VERSION 5.7 ;
  NOWIREEXTENSIONATPIN ON ;
  DIVIDERCHAR "/" ;
  BUSBITCHARS "[]" ;
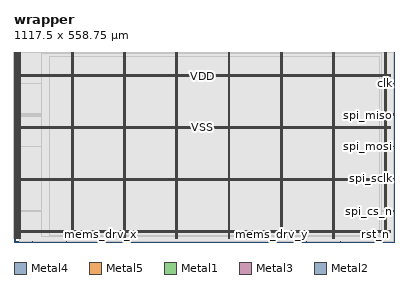
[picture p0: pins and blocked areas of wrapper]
MACRO wrapper
  CLASS BLOCK ;
  FOREIGN wrapper ;
  ORIGIN 0.000 0.000 ;
  SIZE 1117.500 BY 558.750 ;
  PIN VDD
    DIRECTION INOUT ;
    USE POWER ;
    PORT
      LAYER Metal4 ;
        RECT 15.520 11.460 17.120 556.940 ;
    END
    PORT
      LAYER Metal4 ;
        RECT 169.120 11.460 170.720 556.940 ;
    END
    PORT
      LAYER Metal4 ;
        RECT 322.720 11.460 324.320 556.940 ;
    END
    PORT
      LAYER Metal4 ;
        RECT 476.320 11.460 477.920 556.940 ;
    END
    PORT
      LAYER Metal4 ;
        RECT 629.920 11.460 631.520 556.940 ;
    END
    PORT
      LAYER Metal4 ;
        RECT 783.520 11.460 785.120 556.940 ;
    END
    PORT
      LAYER Metal4 ;
        RECT 937.120 11.460 938.720 556.940 ;
    END
    PORT
      LAYER Metal4 ;
        RECT 1090.720 11.460 1092.320 556.940 ;
    END
    PORT
      LAYER Metal5 ;
        RECT 0.000 27.610 1107.120 29.210 ;
    END
    PORT
      LAYER Metal5 ;
        RECT 0.000 180.790 1107.120 182.390 ;
    END
    PORT
      LAYER Metal5 ;
        RECT 0.000 333.970 1107.120 335.570 ;
    END
    PORT
      LAYER Metal5 ;
        RECT 0.000 487.150 1107.120 488.750 ;
    END
    PORT
      LAYER Metal1 ;
        RECT 0.000 15.380 15.670 15.980 ;
    END
    PORT
      LAYER Metal1 ;
        RECT 0.000 23.220 15.670 23.820 ;
    END
    PORT
      LAYER Metal1 ;
        RECT 0.000 31.060 15.670 31.660 ;
    END
    PORT
      LAYER Metal1 ;
        RECT 0.000 38.900 15.670 39.500 ;
    END
    PORT
      LAYER Metal1 ;
        RECT 0.000 46.740 15.670 47.340 ;
    END
    PORT
      LAYER Metal1 ;
        RECT 0.000 54.580 15.670 55.180 ;
    END
    PORT
      LAYER Metal1 ;
        RECT 0.000 62.420 15.670 63.020 ;
    END
    PORT
      LAYER Metal1 ;
        RECT 0.000 70.260 15.670 70.860 ;
    END
    PORT
      LAYER Metal1 ;
        RECT 0.000 78.100 15.670 78.700 ;
    END
    PORT
      LAYER Metal1 ;
        RECT 0.000 85.940 15.670 86.540 ;
    END
    PORT
      LAYER Metal1 ;
        RECT 0.000 93.780 15.670 94.380 ;
    END
    PORT
      LAYER Metal1 ;
        RECT 0.000 101.620 15.670 102.220 ;
    END
    PORT
      LAYER Metal1 ;
        RECT 0.000 109.460 15.670 110.060 ;
    END
    PORT
      LAYER Metal1 ;
        RECT 0.000 117.300 15.670 117.900 ;
    END
    PORT
      LAYER Metal1 ;
        RECT 0.000 125.140 15.670 125.740 ;
    END
    PORT
      LAYER Metal1 ;
        RECT 0.000 132.980 15.670 133.580 ;
    END
    PORT
      LAYER Metal1 ;
        RECT 0.000 140.820 15.670 141.420 ;
    END
    PORT
      LAYER Metal1 ;
        RECT 0.000 148.660 15.670 149.260 ;
    END
    PORT
      LAYER Metal1 ;
        RECT 0.000 156.500 15.670 157.100 ;
    END
    PORT
      LAYER Metal1 ;
        RECT 0.000 164.340 15.670 164.940 ;
    END
    PORT
      LAYER Metal1 ;
        RECT 0.000 172.180 15.670 172.780 ;
    END
    PORT
      LAYER Metal1 ;
        RECT 0.000 180.020 15.670 180.620 ;
    END
    PORT
      LAYER Metal1 ;
        RECT 0.000 187.860 15.670 188.460 ;
    END
    PORT
      LAYER Metal1 ;
        RECT 0.000 195.700 15.670 196.300 ;
    END
    PORT
      LAYER Metal1 ;
        RECT 0.000 203.540 15.670 204.140 ;
    END
    PORT
      LAYER Metal1 ;
        RECT 0.000 211.380 15.670 211.980 ;
    END
    PORT
      LAYER Metal1 ;
        RECT 0.000 219.220 15.670 219.820 ;
    END
    PORT
      LAYER Metal1 ;
        RECT 0.000 227.060 15.670 227.660 ;
    END
    PORT
      LAYER Metal1 ;
        RECT 0.000 234.900 15.670 235.500 ;
    END
    PORT
      LAYER Metal1 ;
        RECT 0.000 242.740 15.670 243.340 ;
    END
    PORT
      LAYER Metal1 ;
        RECT 0.000 250.580 15.670 251.180 ;
    END
    PORT
      LAYER Metal1 ;
        RECT 0.000 258.420 15.670 259.020 ;
    END
    PORT
      LAYER Metal1 ;
        RECT 0.000 266.260 15.670 266.860 ;
    END
    PORT
      LAYER Metal1 ;
        RECT 0.000 274.100 15.670 274.700 ;
    END
    PORT
      LAYER Metal1 ;
        RECT 0.000 281.940 15.670 282.540 ;
    END
    PORT
      LAYER Metal1 ;
        RECT 0.000 289.780 15.670 290.380 ;
    END
    PORT
      LAYER Metal1 ;
        RECT 0.000 297.620 15.670 298.220 ;
    END
    PORT
      LAYER Metal1 ;
        RECT 0.000 305.460 15.670 306.060 ;
    END
    PORT
      LAYER Metal1 ;
        RECT 0.000 313.300 15.670 313.900 ;
    END
    PORT
      LAYER Metal1 ;
        RECT 0.000 321.140 15.670 321.740 ;
    END
    PORT
      LAYER Metal1 ;
        RECT 0.000 328.980 15.670 329.580 ;
    END
    PORT
      LAYER Metal1 ;
        RECT 0.000 336.820 15.670 337.420 ;
    END
    PORT
      LAYER Metal1 ;
        RECT 0.000 344.660 15.670 345.260 ;
    END
    PORT
      LAYER Metal1 ;
        RECT 0.000 352.500 15.670 353.100 ;
    END
    PORT
      LAYER Metal1 ;
        RECT 0.000 360.340 15.670 360.940 ;
    END
    PORT
      LAYER Metal1 ;
        RECT 0.000 368.180 15.670 368.780 ;
    END
    PORT
      LAYER Metal1 ;
        RECT 0.000 376.020 15.670 376.620 ;
    END
    PORT
      LAYER Metal1 ;
        RECT 0.000 383.860 15.670 384.460 ;
    END
    PORT
      LAYER Metal1 ;
        RECT 0.000 391.700 15.670 392.300 ;
    END
    PORT
      LAYER Metal1 ;
        RECT 0.000 399.540 15.670 400.140 ;
    END
    PORT
      LAYER Metal1 ;
        RECT 0.000 407.380 15.670 407.980 ;
    END
    PORT
      LAYER Metal1 ;
        RECT 0.000 415.220 15.670 415.820 ;
    END
    PORT
      LAYER Metal1 ;
        RECT 0.000 423.060 15.670 423.660 ;
    END
    PORT
      LAYER Metal1 ;
        RECT 0.000 430.900 15.670 431.500 ;
    END
    PORT
      LAYER Metal1 ;
        RECT 0.000 438.740 15.670 439.340 ;
    END
    PORT
      LAYER Metal1 ;
        RECT 0.000 446.580 15.670 447.180 ;
    END
    PORT
      LAYER Metal1 ;
        RECT 0.000 454.420 15.670 455.020 ;
    END
    PORT
      LAYER Metal1 ;
        RECT 0.000 462.260 15.670 462.860 ;
    END
    PORT
      LAYER Metal1 ;
        RECT 0.000 470.100 15.670 470.700 ;
    END
    PORT
      LAYER Metal1 ;
        RECT 0.000 477.940 15.670 478.540 ;
    END
    PORT
      LAYER Metal1 ;
        RECT 0.000 485.780 15.670 486.380 ;
    END
    PORT
      LAYER Metal1 ;
        RECT 0.000 493.620 15.670 494.220 ;
    END
    PORT
      LAYER Metal1 ;
        RECT 0.000 501.460 15.670 502.060 ;
    END
    PORT
      LAYER Metal1 ;
        RECT 0.000 509.300 15.670 509.900 ;
    END
    PORT
      LAYER Metal1 ;
        RECT 0.000 517.140 15.670 517.740 ;
    END
    PORT
      LAYER Metal1 ;
        RECT 0.000 524.980 15.670 525.580 ;
    END
    PORT
      LAYER Metal1 ;
        RECT 0.000 532.820 15.670 533.420 ;
    END
    PORT
      LAYER Metal1 ;
        RECT 0.000 540.660 15.670 541.260 ;
    END
    PORT
      LAYER Metal1 ;
        RECT 0.000 548.500 15.670 549.100 ;
    END
    PORT
      LAYER Metal1 ;
        RECT 0.000 556.340 15.670 556.940 ;
    END
  END VDD
  PIN VSS
    DIRECTION INOUT ;
    USE GROUND ;
    PORT
      LAYER Metal4 ;
        RECT 18.820 11.460 20.420 556.940 ;
    END
    PORT
      LAYER Metal4 ;
        RECT 172.420 11.460 174.020 556.940 ;
    END
    PORT
      LAYER Metal4 ;
        RECT 326.020 11.460 327.620 556.940 ;
    END
    PORT
      LAYER Metal4 ;
        RECT 479.620 11.460 481.220 556.940 ;
    END
    PORT
      LAYER Metal4 ;
        RECT 633.220 11.460 634.820 556.940 ;
    END
    PORT
      LAYER Metal4 ;
        RECT 786.820 11.460 788.420 556.940 ;
    END
    PORT
      LAYER Metal4 ;
        RECT 940.420 11.460 942.020 556.940 ;
    END
    PORT
      LAYER Metal4 ;
        RECT 1094.020 11.460 1095.620 556.940 ;
    END
    PORT
      LAYER Metal5 ;
        RECT 0.000 30.910 1107.120 32.510 ;
    END
    PORT
      LAYER Metal5 ;
        RECT 0.000 184.090 1107.120 185.690 ;
    END
    PORT
      LAYER Metal5 ;
        RECT 0.000 337.270 1107.120 338.870 ;
    END
    PORT
      LAYER Metal5 ;
        RECT 0.000 490.450 1107.120 492.050 ;
    END
    PORT
      LAYER Metal1 ;
        RECT 0.000 11.460 18.970 12.060 ;
    END
    PORT
      LAYER Metal1 ;
        RECT 0.000 19.300 18.970 19.900 ;
    END
    PORT
      LAYER Metal1 ;
        RECT 0.000 27.140 18.970 27.740 ;
    END
    PORT
      LAYER Metal1 ;
        RECT 0.000 34.980 18.970 35.580 ;
    END
    PORT
      LAYER Metal1 ;
        RECT 0.000 42.820 18.970 43.420 ;
    END
    PORT
      LAYER Metal1 ;
        RECT 0.000 50.660 18.970 51.260 ;
    END
    PORT
      LAYER Metal1 ;
        RECT 0.000 58.500 18.970 59.100 ;
    END
    PORT
      LAYER Metal1 ;
        RECT 0.000 66.340 18.970 66.940 ;
    END
    PORT
      LAYER Metal1 ;
        RECT 0.000 74.180 18.970 74.780 ;
    END
    PORT
      LAYER Metal1 ;
        RECT 0.000 82.020 18.970 82.620 ;
    END
    PORT
      LAYER Metal1 ;
        RECT 0.000 89.860 18.970 90.460 ;
    END
    PORT
      LAYER Metal1 ;
        RECT 0.000 97.700 18.970 98.300 ;
    END
    PORT
      LAYER Metal1 ;
        RECT 0.000 105.540 18.970 106.140 ;
    END
    PORT
      LAYER Metal1 ;
        RECT 0.000 113.380 18.970 113.980 ;
    END
    PORT
      LAYER Metal1 ;
        RECT 0.000 121.220 18.970 121.820 ;
    END
    PORT
      LAYER Metal1 ;
        RECT 0.000 129.060 18.970 129.660 ;
    END
    PORT
      LAYER Metal1 ;
        RECT 0.000 136.900 18.970 137.500 ;
    END
    PORT
      LAYER Metal1 ;
        RECT 0.000 144.740 18.970 145.340 ;
    END
    PORT
      LAYER Metal1 ;
        RECT 0.000 152.580 18.970 153.180 ;
    END
    PORT
      LAYER Metal1 ;
        RECT 0.000 160.420 18.970 161.020 ;
    END
    PORT
      LAYER Metal1 ;
        RECT 0.000 168.260 18.970 168.860 ;
    END
    PORT
      LAYER Metal1 ;
        RECT 0.000 176.100 18.970 176.700 ;
    END
    PORT
      LAYER Metal1 ;
        RECT 0.000 183.940 18.970 184.540 ;
    END
    PORT
      LAYER Metal1 ;
        RECT 0.000 191.780 18.970 192.380 ;
    END
    PORT
      LAYER Metal1 ;
        RECT 0.000 199.620 18.970 200.220 ;
    END
    PORT
      LAYER Metal1 ;
        RECT 0.000 207.460 18.970 208.060 ;
    END
    PORT
      LAYER Metal1 ;
        RECT 0.000 215.300 18.970 215.900 ;
    END
    PORT
      LAYER Metal1 ;
        RECT 0.000 223.140 18.970 223.740 ;
    END
    PORT
      LAYER Metal1 ;
        RECT 0.000 230.980 18.970 231.580 ;
    END
    PORT
      LAYER Metal1 ;
        RECT 0.000 238.820 18.970 239.420 ;
    END
    PORT
      LAYER Metal1 ;
        RECT 0.000 246.660 18.970 247.260 ;
    END
    PORT
      LAYER Metal1 ;
        RECT 0.000 254.500 18.970 255.100 ;
    END
    PORT
      LAYER Metal1 ;
        RECT 0.000 262.340 18.970 262.940 ;
    END
    PORT
      LAYER Metal1 ;
        RECT 0.000 270.180 18.970 270.780 ;
    END
    PORT
      LAYER Metal1 ;
        RECT 0.000 278.020 18.970 278.620 ;
    END
    PORT
      LAYER Metal1 ;
        RECT 0.000 285.860 18.970 286.460 ;
    END
    PORT
      LAYER Metal1 ;
        RECT 0.000 293.700 18.970 294.300 ;
    END
    PORT
      LAYER Metal1 ;
        RECT 0.000 301.540 18.970 302.140 ;
    END
    PORT
      LAYER Metal1 ;
        RECT 0.000 309.380 18.970 309.980 ;
    END
    PORT
      LAYER Metal1 ;
        RECT 0.000 317.220 18.970 317.820 ;
    END
    PORT
      LAYER Metal1 ;
        RECT 0.000 325.060 18.970 325.660 ;
    END
    PORT
      LAYER Metal1 ;
        RECT 0.000 332.900 18.970 333.500 ;
    END
    PORT
      LAYER Metal1 ;
        RECT 0.000 340.740 18.970 341.340 ;
    END
    PORT
      LAYER Metal1 ;
        RECT 0.000 348.580 18.970 349.180 ;
    END
    PORT
      LAYER Metal1 ;
        RECT 0.000 356.420 18.970 357.020 ;
    END
    PORT
      LAYER Metal1 ;
        RECT 0.000 364.260 18.970 364.860 ;
    END
    PORT
      LAYER Metal1 ;
        RECT 0.000 372.100 18.970 372.700 ;
    END
    PORT
      LAYER Metal1 ;
        RECT 0.000 379.940 18.970 380.540 ;
    END
    PORT
      LAYER Metal1 ;
        RECT 0.000 387.780 18.970 388.380 ;
    END
    PORT
      LAYER Metal1 ;
        RECT 0.000 395.620 18.970 396.220 ;
    END
    PORT
      LAYER Metal1 ;
        RECT 0.000 403.460 18.970 404.060 ;
    END
    PORT
      LAYER Metal1 ;
        RECT 0.000 411.300 18.970 411.900 ;
    END
    PORT
      LAYER Metal1 ;
        RECT 0.000 419.140 18.970 419.740 ;
    END
    PORT
      LAYER Metal1 ;
        RECT 0.000 426.980 18.970 427.580 ;
    END
    PORT
      LAYER Metal1 ;
        RECT 0.000 434.820 18.970 435.420 ;
    END
    PORT
      LAYER Metal1 ;
        RECT 0.000 442.660 18.970 443.260 ;
    END
    PORT
      LAYER Metal1 ;
        RECT 0.000 450.500 18.970 451.100 ;
    END
    PORT
      LAYER Metal1 ;
        RECT 0.000 458.340 18.970 458.940 ;
    END
    PORT
      LAYER Metal1 ;
        RECT 0.000 466.180 18.970 466.780 ;
    END
    PORT
      LAYER Metal1 ;
        RECT 0.000 474.020 18.970 474.620 ;
    END
    PORT
      LAYER Metal1 ;
        RECT 0.000 481.860 18.970 482.460 ;
    END
    PORT
      LAYER Metal1 ;
        RECT 0.000 489.700 18.970 490.300 ;
    END
    PORT
      LAYER Metal1 ;
        RECT 0.000 497.540 18.970 498.140 ;
    END
    PORT
      LAYER Metal1 ;
        RECT 0.000 505.380 18.970 505.980 ;
    END
    PORT
      LAYER Metal1 ;
        RECT 0.000 513.220 18.970 513.820 ;
    END
    PORT
      LAYER Metal1 ;
        RECT 0.000 521.060 18.970 521.660 ;
    END
    PORT
      LAYER Metal1 ;
        RECT 0.000 528.900 18.970 529.500 ;
    END
    PORT
      LAYER Metal1 ;
        RECT 0.000 536.740 18.970 537.340 ;
    END
    PORT
      LAYER Metal1 ;
        RECT 0.000 544.580 18.970 545.180 ;
    END
    PORT
      LAYER Metal1 ;
        RECT 0.000 552.420 18.970 553.020 ;
    END
  END VSS
  PIN clk
    DIRECTION INPUT ;
    USE SIGNAL ;
    ANTENNAGATEAREA 9.476000 ;
    ANTENNADIFFAREA 0.820800 ;
    PORT
      LAYER Metal3 ;
        RECT 1116.940 465.920 1117.500 466.480 ;
    END
  END clk
  PIN dir_x
    DIRECTION OUTPUT ;
    USE SIGNAL ;
    ANTENNADIFFAREA 1.182800 ;
    PORT
      LAYER Metal2 ;
        RECT 154.560 0.000 155.120 0.560 ;
    END
  END dir_x
  PIN dir_y
    DIRECTION OUTPUT ;
    USE SIGNAL ;
    ANTENNADIFFAREA 1.182800 ;
    PORT
      LAYER Metal2 ;
        RECT 860.160 0.000 860.720 0.560 ;
    END
  END dir_y
  PIN mems_drv_x
    DIRECTION OUTPUT ;
    USE SIGNAL ;
    ANTENNADIFFAREA 1.182800 ;
    PORT
      LAYER Metal2 ;
        RECT 255.360 0.000 255.920 0.560 ;
    END
  END mems_drv_x
  PIN mems_drv_y
    DIRECTION OUTPUT ;
    USE SIGNAL ;
    ANTENNADIFFAREA 1.182800 ;
    PORT
      LAYER Metal2 ;
        RECT 759.360 0.000 759.920 0.560 ;
    END
  END mems_drv_y
  PIN move_en_x
    DIRECTION OUTPUT ;
    USE SIGNAL ;
    ANTENNADIFFAREA 1.182800 ;
    PORT
      LAYER Metal2 ;
        RECT 53.760 0.000 54.320 0.560 ;
    END
  END move_en_x
  PIN move_en_y
    DIRECTION OUTPUT ;
    USE SIGNAL ;
    ANTENNADIFFAREA 1.182800 ;
    PORT
      LAYER Metal2 ;
        RECT 960.960 0.000 961.520 0.560 ;
    END
  END move_en_y
  PIN rst_n
    DIRECTION INPUT ;
    USE SIGNAL ;
    ANTENNAGATEAREA 0.498500 ;
    ANTENNADIFFAREA 0.410400 ;
    PORT
      LAYER Metal2 ;
        RECT 1061.760 0.000 1062.320 0.560 ;
    END
  END rst_n
  PIN spi_cs_n
    DIRECTION INPUT ;
    USE SIGNAL ;
    ANTENNAGATEAREA 0.498500 ;
    ANTENNADIFFAREA 0.410400 ;
    PORT
      LAYER Metal3 ;
        RECT 1116.940 90.720 1117.500 91.280 ;
    END
  END spi_cs_n
  PIN spi_miso
    DIRECTION OUTPUT ;
    USE SIGNAL ;
    ANTENNADIFFAREA 1.182800 ;
    PORT
      LAYER Metal3 ;
        RECT 1116.940 370.720 1117.500 371.280 ;
    END
  END spi_miso
  PIN spi_miso_oe
    DIRECTION OUTPUT ;
    USE SIGNAL ;
    ANTENNADIFFAREA 1.182800 ;
    PORT
      LAYER Metal3 ;
        RECT 1116.940 376.320 1117.500 376.880 ;
    END
  END spi_miso_oe
  PIN spi_mosi
    DIRECTION INPUT ;
    USE SIGNAL ;
    ANTENNAGATEAREA 0.498500 ;
    ANTENNADIFFAREA 0.410400 ;
    PORT
      LAYER Metal3 ;
        RECT 1116.940 281.120 1117.500 281.680 ;
    END
  END spi_mosi
  PIN spi_sclk
    DIRECTION INPUT ;
    USE SIGNAL ;
    ANTENNAGATEAREA 0.498500 ;
    ANTENNADIFFAREA 0.410400 ;
    PORT
      LAYER Metal3 ;
        RECT 1116.940 185.920 1117.500 186.480 ;
    END
  END spi_sclk
  OBS
      LAYER Nwell ;
        RECT -0.430 554.480 1107.550 557.070 ;
      LAYER Pwell ;
        RECT -0.430 550.960 1107.550 554.480 ;
      LAYER Nwell ;
        RECT -0.430 546.640 1107.550 550.960 ;
      LAYER Pwell ;
        RECT -0.430 543.120 1107.550 546.640 ;
      LAYER Nwell ;
        RECT -0.430 538.800 1107.550 543.120 ;
      LAYER Pwell ;
        RECT -0.430 535.280 1107.550 538.800 ;
      LAYER Nwell ;
        RECT -0.430 530.960 1107.550 535.280 ;
      LAYER Pwell ;
        RECT -0.430 527.440 1107.550 530.960 ;
      LAYER Nwell ;
        RECT -0.430 523.120 1107.550 527.440 ;
      LAYER Pwell ;
        RECT -0.430 519.600 1107.550 523.120 ;
      LAYER Nwell ;
        RECT -0.430 515.280 1107.550 519.600 ;
      LAYER Pwell ;
        RECT -0.430 511.760 1107.550 515.280 ;
      LAYER Nwell ;
        RECT -0.430 507.440 1107.550 511.760 ;
      LAYER Pwell ;
        RECT -0.430 503.920 1107.550 507.440 ;
      LAYER Nwell ;
        RECT -0.430 499.600 1107.550 503.920 ;
      LAYER Pwell ;
        RECT -0.430 496.080 1107.550 499.600 ;
      LAYER Nwell ;
        RECT -0.430 491.760 1107.550 496.080 ;
      LAYER Pwell ;
        RECT -0.430 488.240 1107.550 491.760 ;
      LAYER Nwell ;
        RECT -0.430 483.920 1107.550 488.240 ;
      LAYER Pwell ;
        RECT -0.430 480.400 1107.550 483.920 ;
      LAYER Nwell ;
        RECT -0.430 476.080 1107.550 480.400 ;
      LAYER Pwell ;
        RECT -0.430 472.560 1107.550 476.080 ;
      LAYER Nwell ;
        RECT -0.430 468.240 1107.550 472.560 ;
      LAYER Pwell ;
        RECT -0.430 464.720 1107.550 468.240 ;
      LAYER Nwell ;
        RECT -0.430 460.400 1107.550 464.720 ;
      LAYER Pwell ;
        RECT -0.430 456.880 1107.550 460.400 ;
      LAYER Nwell ;
        RECT -0.430 452.560 1107.550 456.880 ;
      LAYER Pwell ;
        RECT -0.430 449.040 1107.550 452.560 ;
      LAYER Nwell ;
        RECT -0.430 444.720 1107.550 449.040 ;
      LAYER Pwell ;
        RECT -0.430 441.200 1107.550 444.720 ;
      LAYER Nwell ;
        RECT -0.430 436.880 1107.550 441.200 ;
      LAYER Pwell ;
        RECT -0.430 433.360 1107.550 436.880 ;
      LAYER Nwell ;
        RECT -0.430 429.040 1107.550 433.360 ;
      LAYER Pwell ;
        RECT -0.430 425.520 1107.550 429.040 ;
      LAYER Nwell ;
        RECT -0.430 421.200 1107.550 425.520 ;
      LAYER Pwell ;
        RECT -0.430 417.680 1107.550 421.200 ;
      LAYER Nwell ;
        RECT -0.430 413.360 1107.550 417.680 ;
      LAYER Pwell ;
        RECT -0.430 409.840 1107.550 413.360 ;
      LAYER Nwell ;
        RECT -0.430 405.520 1107.550 409.840 ;
      LAYER Pwell ;
        RECT -0.430 402.000 1107.550 405.520 ;
      LAYER Nwell ;
        RECT -0.430 397.680 1107.550 402.000 ;
      LAYER Pwell ;
        RECT -0.430 394.160 1107.550 397.680 ;
      LAYER Nwell ;
        RECT -0.430 389.840 1107.550 394.160 ;
      LAYER Pwell ;
        RECT -0.430 386.320 1107.550 389.840 ;
      LAYER Nwell ;
        RECT -0.430 382.000 1107.550 386.320 ;
      LAYER Pwell ;
        RECT -0.430 378.480 1107.550 382.000 ;
      LAYER Nwell ;
        RECT -0.430 374.160 1107.550 378.480 ;
      LAYER Pwell ;
        RECT -0.430 370.640 1107.550 374.160 ;
      LAYER Nwell ;
        RECT -0.430 366.320 1107.550 370.640 ;
      LAYER Pwell ;
        RECT -0.430 362.800 1107.550 366.320 ;
      LAYER Nwell ;
        RECT -0.430 358.480 1107.550 362.800 ;
      LAYER Pwell ;
        RECT -0.430 354.960 1107.550 358.480 ;
      LAYER Nwell ;
        RECT -0.430 350.640 1107.550 354.960 ;
      LAYER Pwell ;
        RECT -0.430 347.120 1107.550 350.640 ;
      LAYER Nwell ;
        RECT -0.430 342.800 1107.550 347.120 ;
      LAYER Pwell ;
        RECT -0.430 339.280 1107.550 342.800 ;
      LAYER Nwell ;
        RECT -0.430 334.960 1107.550 339.280 ;
      LAYER Pwell ;
        RECT -0.430 331.440 1107.550 334.960 ;
      LAYER Nwell ;
        RECT -0.430 327.120 1107.550 331.440 ;
      LAYER Pwell ;
        RECT -0.430 323.600 1107.550 327.120 ;
      LAYER Nwell ;
        RECT -0.430 319.280 1107.550 323.600 ;
      LAYER Pwell ;
        RECT -0.430 315.760 1107.550 319.280 ;
      LAYER Nwell ;
        RECT -0.430 311.440 1107.550 315.760 ;
      LAYER Pwell ;
        RECT -0.430 307.920 1107.550 311.440 ;
      LAYER Nwell ;
        RECT -0.430 303.600 1107.550 307.920 ;
      LAYER Pwell ;
        RECT -0.430 300.080 1107.550 303.600 ;
      LAYER Nwell ;
        RECT -0.430 295.760 1107.550 300.080 ;
      LAYER Pwell ;
        RECT -0.430 292.240 1107.550 295.760 ;
      LAYER Nwell ;
        RECT -0.430 287.920 1107.550 292.240 ;
      LAYER Pwell ;
        RECT -0.430 284.400 1107.550 287.920 ;
      LAYER Nwell ;
        RECT -0.430 280.080 1107.550 284.400 ;
      LAYER Pwell ;
        RECT -0.430 276.560 1107.550 280.080 ;
      LAYER Nwell ;
        RECT -0.430 272.240 1107.550 276.560 ;
      LAYER Pwell ;
        RECT -0.430 268.720 1107.550 272.240 ;
      LAYER Nwell ;
        RECT -0.430 264.400 1107.550 268.720 ;
      LAYER Pwell ;
        RECT -0.430 260.880 1107.550 264.400 ;
      LAYER Nwell ;
        RECT -0.430 256.560 1107.550 260.880 ;
      LAYER Pwell ;
        RECT -0.430 254.370 1107.550 256.560 ;
        RECT -0.430 253.040 258.030 254.370 ;
      LAYER Nwell ;
        RECT 258.030 253.040 1107.550 254.370 ;
        RECT -0.430 248.720 1107.550 253.040 ;
      LAYER Pwell ;
        RECT -0.430 245.200 258.030 248.720 ;
      LAYER Nwell ;
        RECT 258.030 245.200 1107.550 248.720 ;
        RECT -0.430 240.880 1107.550 245.200 ;
      LAYER Pwell ;
        RECT -0.430 237.360 258.030 240.880 ;
      LAYER Nwell ;
        RECT 258.030 237.360 1107.550 240.880 ;
        RECT -0.430 233.040 1107.550 237.360 ;
      LAYER Pwell ;
        RECT -0.430 229.520 258.030 233.040 ;
      LAYER Nwell ;
        RECT 258.030 229.520 1107.550 233.040 ;
        RECT -0.430 225.200 1107.550 229.520 ;
      LAYER Pwell ;
        RECT -0.430 221.680 258.030 225.200 ;
      LAYER Nwell ;
        RECT 258.030 221.680 1107.550 225.200 ;
        RECT -0.430 217.360 1107.550 221.680 ;
      LAYER Pwell ;
        RECT -0.430 213.840 258.030 217.360 ;
      LAYER Nwell ;
        RECT 258.030 213.840 1107.550 217.360 ;
        RECT -0.430 209.520 1107.550 213.840 ;
      LAYER Pwell ;
        RECT -0.430 206.000 258.030 209.520 ;
      LAYER Nwell ;
        RECT 258.030 206.000 1107.550 209.520 ;
        RECT -0.430 201.680 1107.550 206.000 ;
      LAYER Pwell ;
        RECT -0.430 198.160 258.030 201.680 ;
      LAYER Nwell ;
        RECT 258.030 198.160 1107.550 201.680 ;
        RECT -0.430 193.840 1107.550 198.160 ;
      LAYER Pwell ;
        RECT -0.430 190.320 258.030 193.840 ;
      LAYER Nwell ;
        RECT 258.030 190.320 1107.550 193.840 ;
        RECT -0.430 186.000 1107.550 190.320 ;
      LAYER Pwell ;
        RECT -0.430 182.480 258.030 186.000 ;
      LAYER Nwell ;
        RECT 258.030 182.480 1107.550 186.000 ;
        RECT -0.430 178.160 1107.550 182.480 ;
      LAYER Pwell ;
        RECT -0.430 174.640 258.030 178.160 ;
      LAYER Nwell ;
        RECT 258.030 174.640 1107.550 178.160 ;
        RECT -0.430 170.320 1107.550 174.640 ;
      LAYER Pwell ;
        RECT -0.430 166.800 258.030 170.320 ;
      LAYER Nwell ;
        RECT 258.030 166.800 1107.550 170.320 ;
        RECT -0.430 162.480 1107.550 166.800 ;
      LAYER Pwell ;
        RECT -0.430 158.960 258.030 162.480 ;
      LAYER Nwell ;
        RECT 258.030 158.960 1107.550 162.480 ;
        RECT -0.430 154.640 1107.550 158.960 ;
      LAYER Pwell ;
        RECT -0.430 151.120 258.030 154.640 ;
      LAYER Nwell ;
        RECT 258.030 151.120 1107.550 154.640 ;
        RECT -0.430 146.800 1107.550 151.120 ;
      LAYER Pwell ;
        RECT -0.430 143.280 258.030 146.800 ;
      LAYER Nwell ;
        RECT 258.030 143.280 1107.550 146.800 ;
        RECT -0.430 138.960 1107.550 143.280 ;
      LAYER Pwell ;
        RECT -0.430 135.440 258.030 138.960 ;
      LAYER Nwell ;
        RECT 258.030 135.440 1107.550 138.960 ;
        RECT -0.430 131.120 1107.550 135.440 ;
      LAYER Pwell ;
        RECT -0.430 127.600 258.030 131.120 ;
      LAYER Nwell ;
        RECT 258.030 127.600 1107.550 131.120 ;
        RECT -0.430 123.280 1107.550 127.600 ;
      LAYER Pwell ;
        RECT -0.430 119.760 258.030 123.280 ;
      LAYER Nwell ;
        RECT 258.030 119.760 1107.550 123.280 ;
        RECT -0.430 115.440 1107.550 119.760 ;
      LAYER Pwell ;
        RECT -0.430 111.920 258.030 115.440 ;
      LAYER Nwell ;
        RECT 258.030 111.920 1107.550 115.440 ;
        RECT -0.430 107.600 1107.550 111.920 ;
      LAYER Pwell ;
        RECT -0.430 104.080 258.030 107.600 ;
      LAYER Nwell ;
        RECT 258.030 104.080 1107.550 107.600 ;
        RECT -0.430 99.760 1107.550 104.080 ;
      LAYER Pwell ;
        RECT -0.430 96.240 258.030 99.760 ;
      LAYER Nwell ;
        RECT 258.030 96.240 1107.550 99.760 ;
        RECT -0.430 91.920 1107.550 96.240 ;
      LAYER Pwell ;
        RECT -0.430 88.400 258.030 91.920 ;
      LAYER Nwell ;
        RECT 258.030 88.400 1107.550 91.920 ;
        RECT -0.430 84.080 1107.550 88.400 ;
      LAYER Pwell ;
        RECT -0.430 80.560 258.030 84.080 ;
      LAYER Nwell ;
        RECT 258.030 80.560 1107.550 84.080 ;
        RECT -0.430 76.240 1107.550 80.560 ;
      LAYER Pwell ;
        RECT -0.430 72.720 258.030 76.240 ;
      LAYER Nwell ;
        RECT 258.030 72.720 1107.550 76.240 ;
        RECT -0.430 68.400 1107.550 72.720 ;
      LAYER Pwell ;
        RECT -0.430 64.880 258.030 68.400 ;
      LAYER Nwell ;
        RECT 258.030 64.880 1107.550 68.400 ;
        RECT -0.430 60.560 1107.550 64.880 ;
      LAYER Pwell ;
        RECT -0.430 57.040 258.030 60.560 ;
      LAYER Nwell ;
        RECT 258.030 57.040 1107.550 60.560 ;
        RECT -0.430 52.720 1107.550 57.040 ;
      LAYER Pwell ;
        RECT -0.430 49.200 258.030 52.720 ;
      LAYER Nwell ;
        RECT 258.030 49.200 1107.550 52.720 ;
        RECT -0.430 44.880 1107.550 49.200 ;
      LAYER Pwell ;
        RECT -0.430 41.360 258.030 44.880 ;
      LAYER Nwell ;
        RECT 258.030 41.360 1107.550 44.880 ;
        RECT -0.430 37.040 1107.550 41.360 ;
      LAYER Pwell ;
        RECT -0.430 33.520 258.030 37.040 ;
      LAYER Nwell ;
        RECT 258.030 33.520 1107.550 37.040 ;
        RECT -0.430 29.200 1107.550 33.520 ;
      LAYER Pwell ;
        RECT -0.430 25.680 258.030 29.200 ;
      LAYER Nwell ;
        RECT 258.030 25.680 1107.550 29.200 ;
        RECT -0.430 21.360 1107.550 25.680 ;
      LAYER Pwell ;
        RECT -0.430 17.840 258.030 21.360 ;
      LAYER Nwell ;
        RECT 258.030 17.840 1107.550 21.360 ;
        RECT -0.430 13.520 1107.550 17.840 ;
      LAYER Pwell ;
        RECT -0.430 11.330 258.030 13.520 ;
      LAYER Nwell ;
        RECT 258.030 11.330 1107.550 13.520 ;
      LAYER Metal1 ;
        RECT 15.970 556.040 1107.120 556.940 ;
        RECT 0.370 553.320 1107.120 556.040 ;
        RECT 19.270 552.120 1107.120 553.320 ;
        RECT 0.370 549.400 1107.120 552.120 ;
        RECT 15.970 548.200 1107.120 549.400 ;
        RECT 0.370 545.480 1107.120 548.200 ;
        RECT 19.270 544.280 1107.120 545.480 ;
        RECT 0.370 541.560 1107.120 544.280 ;
        RECT 15.970 540.360 1107.120 541.560 ;
        RECT 0.370 537.640 1107.120 540.360 ;
        RECT 19.270 536.440 1107.120 537.640 ;
        RECT 0.370 533.720 1107.120 536.440 ;
        RECT 15.970 532.520 1107.120 533.720 ;
        RECT 0.370 529.800 1107.120 532.520 ;
        RECT 19.270 528.600 1107.120 529.800 ;
        RECT 0.370 525.880 1107.120 528.600 ;
        RECT 15.970 524.680 1107.120 525.880 ;
        RECT 0.370 521.960 1107.120 524.680 ;
        RECT 19.270 520.760 1107.120 521.960 ;
        RECT 0.370 518.040 1107.120 520.760 ;
        RECT 15.970 516.840 1107.120 518.040 ;
        RECT 0.370 514.120 1107.120 516.840 ;
        RECT 19.270 512.920 1107.120 514.120 ;
        RECT 0.370 510.200 1107.120 512.920 ;
        RECT 15.970 509.000 1107.120 510.200 ;
        RECT 0.370 506.280 1107.120 509.000 ;
        RECT 19.270 505.080 1107.120 506.280 ;
        RECT 0.370 502.360 1107.120 505.080 ;
        RECT 15.970 501.160 1107.120 502.360 ;
        RECT 0.370 498.440 1107.120 501.160 ;
        RECT 19.270 497.240 1107.120 498.440 ;
        RECT 0.370 494.520 1107.120 497.240 ;
        RECT 15.970 493.320 1107.120 494.520 ;
        RECT 0.370 490.600 1107.120 493.320 ;
        RECT 19.270 489.400 1107.120 490.600 ;
        RECT 0.370 486.680 1107.120 489.400 ;
        RECT 15.970 485.480 1107.120 486.680 ;
        RECT 0.370 482.760 1107.120 485.480 ;
        RECT 19.270 481.560 1107.120 482.760 ;
        RECT 0.370 478.840 1107.120 481.560 ;
        RECT 15.970 477.640 1107.120 478.840 ;
        RECT 0.370 474.920 1107.120 477.640 ;
        RECT 19.270 473.720 1107.120 474.920 ;
        RECT 0.370 471.000 1107.120 473.720 ;
        RECT 15.970 469.800 1107.120 471.000 ;
        RECT 0.370 467.080 1107.120 469.800 ;
        RECT 19.270 465.880 1107.120 467.080 ;
        RECT 0.370 463.160 1107.120 465.880 ;
        RECT 15.970 461.960 1107.120 463.160 ;
        RECT 0.370 459.240 1107.120 461.960 ;
        RECT 19.270 458.040 1107.120 459.240 ;
        RECT 0.370 455.320 1107.120 458.040 ;
        RECT 15.970 454.120 1107.120 455.320 ;
        RECT 0.370 451.400 1107.120 454.120 ;
        RECT 19.270 450.200 1107.120 451.400 ;
        RECT 0.370 447.480 1107.120 450.200 ;
        RECT 15.970 446.280 1107.120 447.480 ;
        RECT 0.370 443.560 1107.120 446.280 ;
        RECT 19.270 442.360 1107.120 443.560 ;
        RECT 0.370 439.640 1107.120 442.360 ;
        RECT 15.970 438.440 1107.120 439.640 ;
        RECT 0.370 435.720 1107.120 438.440 ;
        RECT 19.270 434.520 1107.120 435.720 ;
        RECT 0.370 431.800 1107.120 434.520 ;
        RECT 15.970 430.600 1107.120 431.800 ;
        RECT 0.370 427.880 1107.120 430.600 ;
        RECT 19.270 426.680 1107.120 427.880 ;
        RECT 0.370 423.960 1107.120 426.680 ;
        RECT 15.970 422.760 1107.120 423.960 ;
        RECT 0.370 420.040 1107.120 422.760 ;
        RECT 19.270 418.840 1107.120 420.040 ;
        RECT 0.370 416.120 1107.120 418.840 ;
        RECT 15.970 414.920 1107.120 416.120 ;
        RECT 0.370 412.200 1107.120 414.920 ;
        RECT 19.270 411.000 1107.120 412.200 ;
        RECT 0.370 408.280 1107.120 411.000 ;
        RECT 15.970 407.080 1107.120 408.280 ;
        RECT 0.370 404.360 1107.120 407.080 ;
        RECT 19.270 403.160 1107.120 404.360 ;
        RECT 0.370 400.440 1107.120 403.160 ;
        RECT 15.970 399.240 1107.120 400.440 ;
        RECT 0.370 396.520 1107.120 399.240 ;
        RECT 19.270 395.320 1107.120 396.520 ;
        RECT 0.370 392.600 1107.120 395.320 ;
        RECT 15.970 391.400 1107.120 392.600 ;
        RECT 0.370 388.680 1107.120 391.400 ;
        RECT 19.270 387.480 1107.120 388.680 ;
        RECT 0.370 384.760 1107.120 387.480 ;
        RECT 15.970 383.560 1107.120 384.760 ;
        RECT 0.370 380.840 1107.120 383.560 ;
        RECT 19.270 379.640 1107.120 380.840 ;
        RECT 0.370 376.920 1107.120 379.640 ;
        RECT 15.970 375.720 1107.120 376.920 ;
        RECT 0.370 373.000 1107.120 375.720 ;
        RECT 19.270 371.800 1107.120 373.000 ;
        RECT 0.370 369.080 1107.120 371.800 ;
        RECT 15.970 367.880 1107.120 369.080 ;
        RECT 0.370 365.160 1107.120 367.880 ;
        RECT 19.270 363.960 1107.120 365.160 ;
        RECT 0.370 361.240 1107.120 363.960 ;
        RECT 15.970 360.040 1107.120 361.240 ;
        RECT 0.370 357.320 1107.120 360.040 ;
        RECT 19.270 356.120 1107.120 357.320 ;
        RECT 0.370 353.400 1107.120 356.120 ;
        RECT 15.970 352.200 1107.120 353.400 ;
        RECT 0.370 349.480 1107.120 352.200 ;
        RECT 19.270 348.280 1107.120 349.480 ;
        RECT 0.370 345.560 1107.120 348.280 ;
        RECT 15.970 344.360 1107.120 345.560 ;
        RECT 0.370 341.640 1107.120 344.360 ;
        RECT 19.270 340.440 1107.120 341.640 ;
        RECT 0.370 337.720 1107.120 340.440 ;
        RECT 15.970 336.520 1107.120 337.720 ;
        RECT 0.370 333.800 1107.120 336.520 ;
        RECT 19.270 332.600 1107.120 333.800 ;
        RECT 0.370 329.880 1107.120 332.600 ;
        RECT 15.970 328.680 1107.120 329.880 ;
        RECT 0.370 325.960 1107.120 328.680 ;
        RECT 19.270 324.760 1107.120 325.960 ;
        RECT 0.370 322.040 1107.120 324.760 ;
        RECT 15.970 320.840 1107.120 322.040 ;
        RECT 0.370 318.120 1107.120 320.840 ;
        RECT 19.270 316.920 1107.120 318.120 ;
        RECT 0.370 314.200 1107.120 316.920 ;
        RECT 15.970 313.000 1107.120 314.200 ;
        RECT 0.370 310.280 1107.120 313.000 ;
        RECT 19.270 309.080 1107.120 310.280 ;
        RECT 0.370 306.360 1107.120 309.080 ;
        RECT 15.970 305.160 1107.120 306.360 ;
        RECT 0.370 302.440 1107.120 305.160 ;
        RECT 19.270 301.240 1107.120 302.440 ;
        RECT 0.370 298.520 1107.120 301.240 ;
        RECT 15.970 297.320 1107.120 298.520 ;
        RECT 0.370 294.600 1107.120 297.320 ;
        RECT 19.270 293.400 1107.120 294.600 ;
        RECT 0.370 290.680 1107.120 293.400 ;
        RECT 15.970 289.480 1107.120 290.680 ;
        RECT 0.370 286.760 1107.120 289.480 ;
        RECT 19.270 285.560 1107.120 286.760 ;
        RECT 0.370 282.840 1107.120 285.560 ;
        RECT 15.970 281.640 1107.120 282.840 ;
        RECT 0.370 278.920 1107.120 281.640 ;
        RECT 19.270 277.720 1107.120 278.920 ;
        RECT 0.370 275.000 1107.120 277.720 ;
        RECT 15.970 273.800 1107.120 275.000 ;
        RECT 0.370 271.080 1107.120 273.800 ;
        RECT 19.270 269.880 1107.120 271.080 ;
        RECT 0.370 267.160 1107.120 269.880 ;
        RECT 15.970 265.960 1107.120 267.160 ;
        RECT 0.370 263.240 1107.120 265.960 ;
        RECT 19.270 262.040 1107.120 263.240 ;
        RECT 0.370 259.320 1107.120 262.040 ;
        RECT 15.970 258.120 1107.120 259.320 ;
        RECT 0.370 255.400 1107.120 258.120 ;
        RECT 19.270 254.200 1107.120 255.400 ;
        RECT 0.370 251.480 1107.120 254.200 ;
        RECT 15.970 250.280 1107.120 251.480 ;
        RECT 0.370 247.560 1107.120 250.280 ;
        RECT 19.270 246.360 1107.120 247.560 ;
        RECT 0.370 243.640 1107.120 246.360 ;
        RECT 15.970 242.440 1107.120 243.640 ;
        RECT 0.370 239.720 1107.120 242.440 ;
        RECT 19.270 238.520 1107.120 239.720 ;
        RECT 0.370 235.800 1107.120 238.520 ;
        RECT 15.970 234.600 1107.120 235.800 ;
        RECT 0.370 231.880 1107.120 234.600 ;
        RECT 19.270 230.680 1107.120 231.880 ;
        RECT 0.370 227.960 1107.120 230.680 ;
        RECT 15.970 226.760 1107.120 227.960 ;
        RECT 0.370 224.040 1107.120 226.760 ;
        RECT 19.270 222.840 1107.120 224.040 ;
        RECT 0.370 220.120 1107.120 222.840 ;
        RECT 15.970 218.920 1107.120 220.120 ;
        RECT 0.370 216.200 1107.120 218.920 ;
        RECT 19.270 215.000 1107.120 216.200 ;
        RECT 0.370 212.280 1107.120 215.000 ;
        RECT 15.970 211.080 1107.120 212.280 ;
        RECT 0.370 208.360 1107.120 211.080 ;
        RECT 19.270 207.160 1107.120 208.360 ;
        RECT 0.370 204.440 1107.120 207.160 ;
        RECT 15.970 203.240 1107.120 204.440 ;
        RECT 0.370 200.520 1107.120 203.240 ;
        RECT 19.270 199.320 1107.120 200.520 ;
        RECT 0.370 196.600 1107.120 199.320 ;
        RECT 15.970 195.400 1107.120 196.600 ;
        RECT 0.370 192.680 1107.120 195.400 ;
        RECT 19.270 191.480 1107.120 192.680 ;
        RECT 0.370 188.760 1107.120 191.480 ;
        RECT 15.970 187.560 1107.120 188.760 ;
        RECT 0.370 184.840 1107.120 187.560 ;
        RECT 19.270 183.640 1107.120 184.840 ;
        RECT 0.370 180.920 1107.120 183.640 ;
        RECT 15.970 179.720 1107.120 180.920 ;
        RECT 0.370 177.000 1107.120 179.720 ;
        RECT 19.270 175.800 1107.120 177.000 ;
        RECT 0.370 173.080 1107.120 175.800 ;
        RECT 15.970 171.880 1107.120 173.080 ;
        RECT 0.370 169.160 1107.120 171.880 ;
        RECT 19.270 167.960 1107.120 169.160 ;
        RECT 0.370 165.240 1107.120 167.960 ;
        RECT 15.970 164.040 1107.120 165.240 ;
        RECT 0.370 161.320 1107.120 164.040 ;
        RECT 19.270 160.120 1107.120 161.320 ;
        RECT 0.370 157.400 1107.120 160.120 ;
        RECT 15.970 156.200 1107.120 157.400 ;
        RECT 0.370 153.480 1107.120 156.200 ;
        RECT 19.270 152.280 1107.120 153.480 ;
        RECT 0.370 149.560 1107.120 152.280 ;
        RECT 15.970 148.360 1107.120 149.560 ;
        RECT 0.370 145.640 1107.120 148.360 ;
        RECT 19.270 144.440 1107.120 145.640 ;
        RECT 0.370 141.720 1107.120 144.440 ;
        RECT 15.970 140.520 1107.120 141.720 ;
        RECT 0.370 137.800 1107.120 140.520 ;
        RECT 19.270 136.600 1107.120 137.800 ;
        RECT 0.370 133.880 1107.120 136.600 ;
        RECT 15.970 132.680 1107.120 133.880 ;
        RECT 0.370 129.960 1107.120 132.680 ;
        RECT 19.270 128.760 1107.120 129.960 ;
        RECT 0.370 126.040 1107.120 128.760 ;
        RECT 15.970 124.840 1107.120 126.040 ;
        RECT 0.370 122.120 1107.120 124.840 ;
        RECT 19.270 120.920 1107.120 122.120 ;
        RECT 0.370 118.200 1107.120 120.920 ;
        RECT 15.970 117.000 1107.120 118.200 ;
        RECT 0.370 114.280 1107.120 117.000 ;
        RECT 19.270 113.080 1107.120 114.280 ;
        RECT 0.370 110.360 1107.120 113.080 ;
        RECT 15.970 109.160 1107.120 110.360 ;
        RECT 0.370 106.440 1107.120 109.160 ;
        RECT 19.270 105.240 1107.120 106.440 ;
        RECT 0.370 102.520 1107.120 105.240 ;
        RECT 15.970 101.320 1107.120 102.520 ;
        RECT 0.370 98.600 1107.120 101.320 ;
        RECT 19.270 97.400 1107.120 98.600 ;
        RECT 0.370 94.680 1107.120 97.400 ;
        RECT 15.970 93.480 1107.120 94.680 ;
        RECT 0.370 90.760 1107.120 93.480 ;
        RECT 19.270 89.560 1107.120 90.760 ;
        RECT 0.370 86.840 1107.120 89.560 ;
        RECT 15.970 85.640 1107.120 86.840 ;
        RECT 0.370 82.920 1107.120 85.640 ;
        RECT 19.270 81.720 1107.120 82.920 ;
        RECT 0.370 79.000 1107.120 81.720 ;
        RECT 15.970 77.800 1107.120 79.000 ;
        RECT 0.370 75.080 1107.120 77.800 ;
        RECT 19.270 73.880 1107.120 75.080 ;
        RECT 0.370 71.160 1107.120 73.880 ;
        RECT 15.970 69.960 1107.120 71.160 ;
        RECT 0.370 67.240 1107.120 69.960 ;
        RECT 19.270 66.040 1107.120 67.240 ;
        RECT 0.370 63.320 1107.120 66.040 ;
        RECT 15.970 62.120 1107.120 63.320 ;
        RECT 0.370 59.400 1107.120 62.120 ;
        RECT 19.270 58.200 1107.120 59.400 ;
        RECT 0.370 55.480 1107.120 58.200 ;
        RECT 15.970 54.280 1107.120 55.480 ;
        RECT 0.370 51.560 1107.120 54.280 ;
        RECT 19.270 50.360 1107.120 51.560 ;
        RECT 0.370 47.640 1107.120 50.360 ;
        RECT 15.970 46.440 1107.120 47.640 ;
        RECT 0.370 43.720 1107.120 46.440 ;
        RECT 19.270 42.520 1107.120 43.720 ;
        RECT 0.370 39.800 1107.120 42.520 ;
        RECT 15.970 38.600 1107.120 39.800 ;
        RECT 0.370 35.880 1107.120 38.600 ;
        RECT 19.270 34.680 1107.120 35.880 ;
        RECT 0.370 31.960 1107.120 34.680 ;
        RECT 15.970 30.760 1107.120 31.960 ;
        RECT 0.370 28.040 1107.120 30.760 ;
        RECT 19.270 26.840 1107.120 28.040 ;
        RECT 0.370 24.120 1107.120 26.840 ;
        RECT 15.970 22.920 1107.120 24.120 ;
        RECT 0.370 20.200 1107.120 22.920 ;
        RECT 19.270 19.000 1107.120 20.200 ;
        RECT 0.370 16.280 1107.120 19.000 ;
        RECT 15.970 15.080 1107.120 16.280 ;
        RECT 0.370 12.360 1107.120 15.080 ;
        RECT 19.270 11.460 1107.120 12.360 ;
      LAYER Metal2 ;
        RECT 15.660 0.860 1105.300 558.230 ;
        RECT 15.660 0.140 53.460 0.860 ;
        RECT 54.620 0.140 154.260 0.860 ;
        RECT 155.420 0.140 255.060 0.860 ;
        RECT 256.220 0.140 759.060 0.860 ;
        RECT 760.220 0.140 859.860 0.860 ;
        RECT 861.020 0.140 960.660 0.860 ;
        RECT 961.820 0.140 1061.460 0.860 ;
        RECT 1062.620 0.140 1105.300 0.860 ;
      LAYER Metal3 ;
        RECT 15.610 466.780 1116.940 558.740 ;
        RECT 15.610 465.620 1116.640 466.780 ;
        RECT 15.610 377.180 1116.940 465.620 ;
        RECT 15.610 376.020 1116.640 377.180 ;
        RECT 15.610 371.580 1116.940 376.020 ;
        RECT 15.610 370.420 1116.640 371.580 ;
        RECT 15.610 281.980 1116.940 370.420 ;
        RECT 15.610 280.820 1116.640 281.980 ;
        RECT 15.610 186.780 1116.940 280.820 ;
        RECT 15.610 185.620 1116.640 186.780 ;
        RECT 15.610 91.580 1116.940 185.620 ;
        RECT 15.610 90.420 1116.640 91.580 ;
        RECT 15.610 0.700 1116.940 90.420 ;
      LAYER Metal4 ;
        RECT 81.900 17.450 168.820 554.870 ;
        RECT 171.020 17.450 172.120 554.870 ;
        RECT 174.320 17.450 322.420 554.870 ;
        RECT 324.620 17.450 325.720 554.870 ;
        RECT 327.920 17.450 476.020 554.870 ;
        RECT 478.220 17.450 479.320 554.870 ;
        RECT 481.520 17.450 629.620 554.870 ;
        RECT 631.820 17.450 632.920 554.870 ;
        RECT 635.120 17.450 783.220 554.870 ;
        RECT 785.420 17.450 786.520 554.870 ;
        RECT 788.720 17.450 936.820 554.870 ;
        RECT 939.020 17.450 940.120 554.870 ;
        RECT 942.320 17.450 1081.780 554.870 ;
      LAYER Metal5 ;
        RECT 103.100 492.650 1074.580 546.970 ;
        RECT 103.100 489.350 1074.580 489.850 ;
        RECT 103.100 339.470 1074.580 486.550 ;
        RECT 103.100 336.170 1074.580 336.670 ;
        RECT 103.100 186.290 1074.580 333.370 ;
        RECT 103.100 182.990 1074.580 183.490 ;
        RECT 103.100 33.110 1074.580 180.190 ;
        RECT 103.100 29.810 1074.580 30.310 ;
        RECT 103.100 18.230 1074.580 27.010 ;
  END
END wrapper
END LIBRARY

